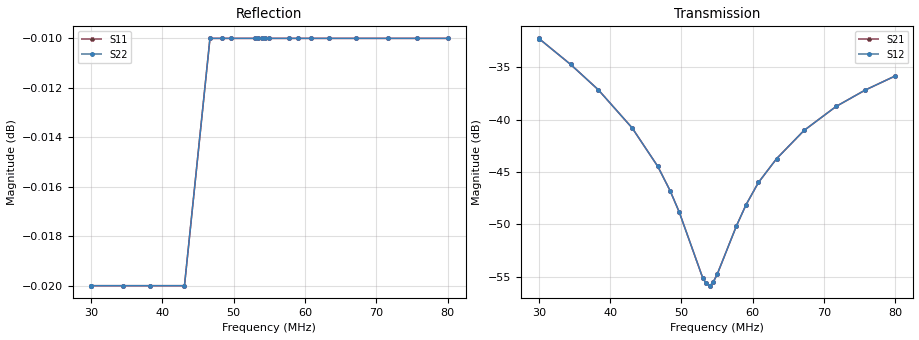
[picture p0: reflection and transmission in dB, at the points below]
!s-Parameter Generated by FASTRON Sdn. Bhd.
!FASTRON P/N : MECC-150X
!Keysight Technologies,E4991B,MY54100416,A.01.15
!Date: Thu Aug 20 13:48:27 2026
!Version  : Rev00 Thu Aug 20 13:48:27 2026
!Data & Calibration Information:
!PortZ  Port1:50+j0  Port2:50+j0
!When reading, reference impedance value at option line is always used.
!Remarks : This data is being provided solely for informational purposes.
!Freq	S11	S21	S12	S22
# Hz S dB R 50
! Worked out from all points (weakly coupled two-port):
!   1601 points, 30 MHz to 80 MHz, reference 50 ohm
!   highest |S21| = -32.24 dB at 30.02 MHz (marker M1); lowest = -55.9 dB at 54.01 MHz (marker M2)
!   lowest |S11| = 0.0 dB at 30.06 MHz (marker M3), VSWR 859.71, Z = 392 + j4.09e+03 ohm
!   |S11| at or under -10 dB: nowhere
!   |S22| runs from 0.0 to 0.0 dB; largest |S21 - S12| = 0
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3e7  -0.02 1.4  -32.26 -83.9  -32.26 -83.9  -0.02 1.4
3.00184e7  -0.02 1.4  -32.24 -83.9  -32.24 -83.9  -0.02 1.4
3.005522e7  -0.02 1.4  -32.28 -83.8  -32.28 -83.8  -0.02 1.4
3.445794e7  -0.02 1.0  -34.73 -82.9  -34.73 -82.9  -0.02 1.0
3.833659e7  -0.02 0.8  -37.15 -81.5  -37.15 -81.5  -0.02 0.8
4.309863e7  -0.02 0.5  -40.81 -78.3  -40.81 -78.3  -0.02 0.5
4.667383e7  -0.01 0.3  -44.47 -73.2  -44.47 -73.2  -0.01 0.3
4.839283e7  -0.01 0.2  -46.78 -68.1  -46.78 -68.1  -0.01 0.2
4.968541e7  -0.01 0.2  -48.84 -61.8  -48.84 -61.8  -0.01 0.2
5.298868e7  -0.01 0.0  -55.15 -23.9  -55.15 -23.9  -0.01 0.0
5.34454e7  -0.01 0.0  -55.63 -13.1  -55.63 -13.1  -0.01 0.0
5.400529e7  -0.01 -0.0  -55.87 2.4  -55.87 2.4  -0.01 -0.0
5.443739e7  -0.01 -0.0  -55.54 13.0  -55.54 13.0  -0.01 -0.0
5.500766e7  -0.01 -0.0  -54.78 25.9  -54.78 25.9  -0.01 -0.0
5.770177e7  -0.01 -0.2  -50.16 58.7  -50.16 58.7  -0.01 -0.2
5.90617e7  -0.01 -0.2  -48.12 65.6  -48.12 65.6  -0.01 -0.2
6.078812e7  -0.01 -0.3  -46.01 71.4  -46.01 71.4  -0.01 -0.3
6.333681e7  -0.01 -0.4  -43.73 76.0  -43.73 76.0  -0.01 -0.4
6.717603e7  -0.01 -0.5  -41.04 79.6  -41.04 79.6  -0.01 -0.5
7.168606e7  -0.01 -0.7  -38.74 82.0  -38.74 82.0  -0.01 -0.7
7.575224e7  -0.01 -0.8  -37.18 83.0  -37.18 83.0  -0.01 -0.8
8e7  -0.01 -0.9  -35.82 83.7  -35.82 83.7  -0.01 -0.9
